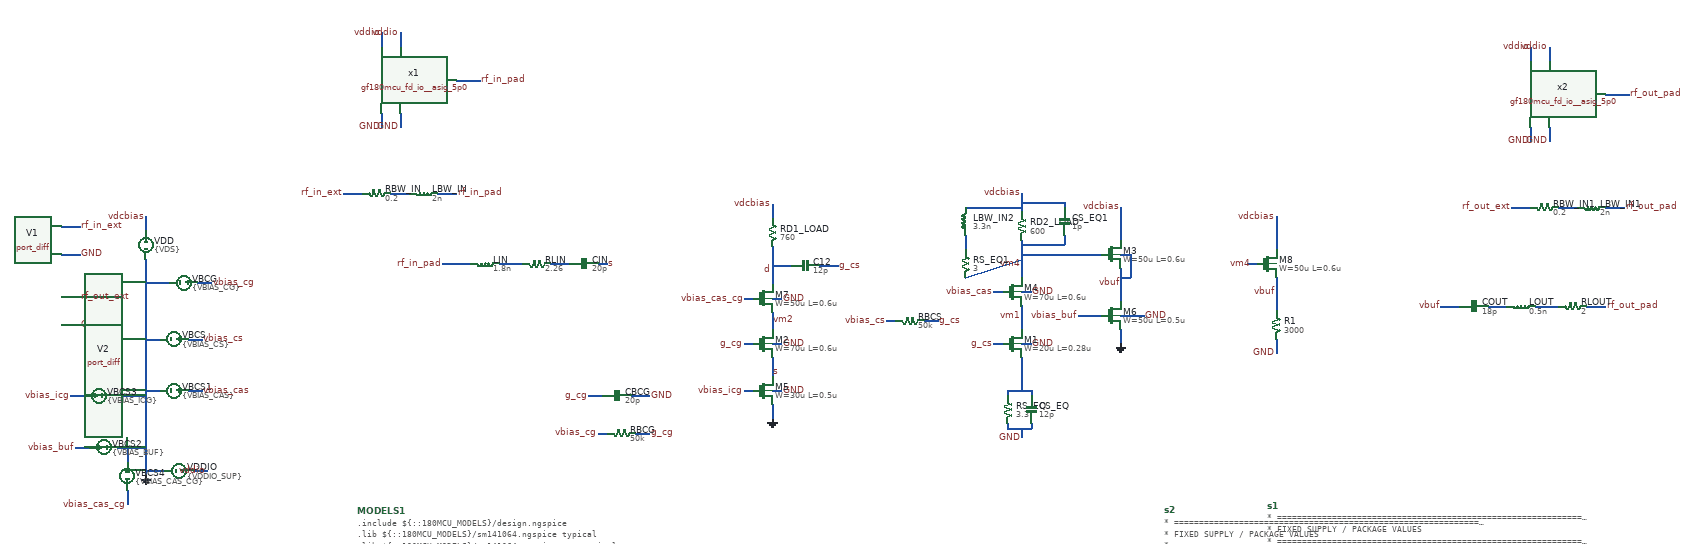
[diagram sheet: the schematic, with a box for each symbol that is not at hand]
v {xschem version=3.4.8RC file_version=1.3}
G {}
K {}
V {}
S {}
F {}
E {}
N -320 -440 -320 -410 {
lab=GND}
N 1010 -260 1030 -260 {
lab=GND}
N -320 -410 -320 -310 {
lab=GND}
N -320 -530 -320 -500 {
lab=vdcbias}
N -320 -390 -270 -390 {
lab=GND}
N -500 -510 -460 -510 {
lab=rf_in_ext}
N -500 -450 -460 -450 {
lab=GND}
N -500 -360 -460 -360 {
lab=rf_out_ext}
N -500 -300 -460 -300 {
lab=GND}
N 1010 -466.25 1010 -386.25 {
lab=d}
N 1010 -556.25 1010 -526.25 {
lab=vdcbias}
N -210 -390 -180 -390 {
lab=vbias_cg}
N 640 -430 660 -430 {
lab=s}
N 310 -430 340 -430 {
lab=rf_in_pad}
N 1010 -426.25 1050 -426.25 {
lab=d}
N 1110 -426.25 1150 -426.25 {
lab=g_cs}
N 1010 -230 1010 -220 {
lab=s}
N 1010 -220 1010 -190 {
lab=s}
N 950 -260 970 -260 {
lab=g_cg}
N -320 -310 -320 -110 {
lab=GND}
N 640 -70 660 -70 {
lab=vbias_cg}
N 720 -70 750 -70 {
lab=g_cg}
N 620 -150 650 -150 {
lab=g_cg}
N 710 -150 750 -150 {
lab=GND}
N 300 -580 340 -580 {
lab=rf_in_pad}
N 200 -580 240 -580 {
lab=rf_in_ext}
N 100 -580 140 -580 {
lab=rf_in_ext}
N 340 -820 390 -820 {
lab=rf_in_pad
}
N 180 -750 180 -720 {
lab=GND
}
N 220 -750 220 -720 {
lab=GND
}
N 180 -920 180 -890 {
lab=vddio
}
N 220 -920 220 -890 {
lab=vddio
}
N -320 -270 -290 -270 {
lab=GND}
N -220 10 -190 10 {
lab=vddio}
N 2780 -790 2830 -790 {
lab=rf_out_pad
}
N 2620 -720 2620 -690 {
lab=GND
}
N 2660 -720 2660 -690 {
lab=GND
}
N 2620 -890 2620 -860 {
lab=vddio
}
N 2660 -890 2660 -860 {
lab=vddio
}
N 2780 -550 2820 -550 {
lab=rf_out_pad}
N 2680 -550 2720 -550 {
lab=#net1}
N 2580 -550 2620 -550 {
lab=rf_out_ext}
N -320 10 -280 10 {
lab=GND}
N -230 -270 -200 -270 {
lab=vbias_cs}
N 1540 -260 1560 -260 {
lab=GND}
N 1540 -230 1540 -220 {
lab=#net2}
N 1480 -260 1500 -260 {
lab=g_cs}
N 1252.5 -308.75 1272.5 -308.75 {
lab=vbias_cs}
N 1332.5 -308.75 1362.5 -308.75 {
lab=g_cs}
N 1540 -220 1540 -160 {
lab=#net2}
N 1540 -580 1540 -540 {
lab=vdcbias}
N 1750 -550 1750 -480 {
lab=vdcbias
}
N 1750 -420 1750 -350 {
lab=vbuf
}
N 1750 -290 1750 -260 {
lab=GND
}
N 1750 -450 1770 -450 {
lab=vbuf
}
N 2430 -340 2470 -340 {
lab=vbuf}
N 2530 -340 2570 -340 {
lab=#net3}
N 2630 -340 2680 -340 {
lab=#net4}
N 2740 -340 2780 -340 {
lab=rf_out_pad}
N 340 -430 370 -430 {
lab=rf_in_pad}
N 430 -430 480 -430 {
lab=rf_in_pad}
N 540 -430 580 -430 {
lab=rf_in_pad}
N 1540 -370 1560 -370 {
lab=GND}
N 1480 -370 1500 -370 {
lab=vbias_cas}
N 1540 -480 1540 -400 {
lab=vm4}
N -320 -110 -320 20 {
lab=GND}
N -230 -160 -200 -160 {
lab=vbias_cas}
N -320 -160 -290 -160 {
lab=GND}
N 1770 -450 1770 -400 {
lab=vbuf
}
N 1750 -400 1770 -400 {
lab=vbuf
}
N 1010 -160 1030 -160 {
lab=GND}
N 1010 -130 1010 -120 {
lab=GND}
N 950 -160 970 -160 {
lab=vbias_icg}
N 1010 -120 1010 -100 {
lab=GND}
N 1660 -320 1710 -320 {
lab=vbias_buf
}
N 1750 -320 1800 -320 {
lab=GND
}
N -470 -40 -440 -40 {
lab=vbias_buf}
N -380 -40 -320 -40 {
lab=GND}
N -480 -150 -450 -150 {
lab=vbias_icg}
N -390 -150 -320 -150 {
lab=GND}
N 1560 -160 1560 -150 {
lab=#net2}
N 1510 -160 1560 -160 {
lab=#net2}
N 1560 -90 1560 -80 {
lab=GND}
N 1510 -80 1560 -80 {
lab=GND}
N 1510 -160 1510 -150 {
lab=#net2}
N 1510 -90 1510 -80 {
lab=GND}
N 1540 -80 1540 -60 {
lab=GND}
N 1670 -450 1710 -450 {
lab=vm4
}
N 1010 -356.25 1030 -356.25 {
lab=d}
N 951.25 -356.25 971.25 -356.25 {
lab=d}
N -360 51.25 -360 81.25 {
lab=vbias_cas_cg}
N 1540 -341.25 1540 -288.75 {
lab=vm1}
N 1010 -326.25 1010 -288.75 {
lab=d}
N -360 -40 -360 -8.75 {
lab=GND}
N 1540 -450 1670 -450 {
lab=vm4
spice_ignore=short}
N 2080 -530 2080 -460 {
lab=vdcbias
spice_ignore=true}
N 2080 -400 2080 -330 {
lab=vbuf
spice_ignore=true}
N 2020 -430 2040 -430 {lab=vm4
spice_ignore=true}
N 2080 -270 2080 -240 {lab=GND
spice_ignore=true}
N 1420 -550 1540 -550 {lab=vdcbias}
N 1540 -560 1630 -560 {lab=vdcbias}
N 1630 -560 1630 -550 {lab=vdcbias}
N 1630 -490 1630 -470 {lab=vm4}
N 1540 -470 1630 -470 {lab=vm4}
N 1420 -490 1420 -460 {lab=vm4}
N 1420 -400 1540 -440 {lab=vm4}
C {vsource.sym} -240 -390 1 0 {name=VBCG value=\{VBIAS_CG\} savecurrent=false}
C {gnd.sym} 1010 -100 0 0 {name=l1 lab=GND}
C {vsource.sym} -320 -470 0 0 {name=VDD value=\{VDS\} savecurrent=false}
C {capa.sym} 1080 -426.25 3 0 {name=C12
m=1
value=12p
footprint=1206
device="ceramic capacitor"}
C {lab_pin.sym} 1010 -416.25 0 0 {name=p3 sig_type=std_logic lab=d}
C {lab_pin.sym} -460 -510 2 0 {name=p5 sig_type=std_logic lab=rf_in_ext}
C {lab_pin.sym} -460 -450 2 0 {name=p6 sig_type=std_logic lab=GND

}
C {lab_pin.sym} -460 -300 2 0 {name=p8 sig_type=std_logic lab=GND}
C {capa.sym} 610 -430 3 0 {name=CIN
m=1
value=20p
footprint=1206
device="ceramic capacitor"}
C {gnd.sym} -320 20 0 0 {name=l3 lab=GND}
C {lab_pin.sym} -320 -530 0 0 {name=p10 sig_type=std_logic lab=vdcbias
}
C {lab_pin.sym} -180 -390 2 0 {name=p9 sig_type=std_logic lab=vbias_cg}
C {lab_pin.sym} 1010 -556.25 0 0 {name=p11 sig_type=std_logic lab=vdcbias
}
C {lab_pin.sym} 1150 -426.25 2 0 {name=p14 sig_type=std_logic lab=g_cs}
C {port_diff.sym} -500 -480 0 0 {name=V1 portnum=1 Z0=50 DCval=0 ACmag=1 ACphase=0 TRANval=""}
C {port_diff.sym} -500 -330 0 0 {name=V2 portnum=2 Z0=50 DCval=0 ACmag=1 ACphase=0 TRANval=""}
C {lab_pin.sym} 1010 -200 2 0 {name=p1 sig_type=std_logic lab=s}
C {lab_pin.sym} 1030 -260 2 0 {name=p2 sig_type=std_logic lab=GND}
C {code.sym} 1842.5 93.75 0 0 {name=s2 only_toplevel=false value="


* =============================================================================
* FIXED SUPPLY / PACKAGE VALUES
* =============================================================================

.param VDS=5.0
.param VDDIO_SUP=5.0
.param L_BW=2n
.param R_BW=0.2


* =============================================================================
* FIXED INPUT NETWORK
* =============================================================================

.param L_IN=1.80n
.param R_L_IN=1.5
.param CIN_VAL=100p
.param C_SH_IN=1f


* =============================================================================
* FIXED XM2 COMMON-GATE INPUT STAGE
* =============================================================================

.param VBIAS_CG=2.20
.param W_CG=140u
.param M_CG=2
.param L_CG=0.60u
.param RD1=760
.param RBIAS_CG=50k
.param CBYP_CG=20p


* =============================================================================
* FIXED MIXED-VOLTAGE XM1/XM4 STAGE
* =============================================================================

.param C12_VAL=33p

.param VBIAS_CS=1.05
.param W_CS=40u
.param M_CS=2
.param L_CS=0.28u
.param RBIAS_CS=50k

.param VBIAS_CAS=3.30
.param W_CAS=70u
.param M_CAS=1
.param L_CAS=0.60u
.param RD2=490

.param RS_EQ=7
.param CSEQ_VAL=12p


* =============================================================================
* FIXED BODY-TIED SOURCE FOLLOWER
* =============================================================================

.param W_SF=125u
.param M_SF=2
.param L_SF=0.60u
.param RG_SF_VAL=0.01


* =============================================================================
* FIXED OUTPUT NETWORK
* =============================================================================

.param COUT_VAL=56p
.param L_OUT=0.20n
.param R_L_OUT=1.5
.param C_SH_OUT=1f


* =============================================================================
* FIXED XM5 COMMON-GATE CURRENT SINK
* =============================================================================

.param VBIAS_ICG=1.55
.param L_BIAS_CG=0.50u
.param W_BIAS_CG=30u
.param M_BIAS_CG=1


* =============================================================================
* FIXED XM6 SOURCE-FOLLOWER CURRENT SINK
* =============================================================================

.param VBIAS_BUF=2.40
.param L_BIAS_SF=0.50u
.param W_BIAS_SF=50u
.param M_BIAS_SF=3


* =============================================================================
* XM7 CG-CASCODE SWEEP PARAMETERS
* =============================================================================

.param VBIAS_CAS_CG=3.40
.param L_CAS_CG=0.60u
.param W_CAS_CG=50u
.param M_CAS_CG=2

* =============================================================================
* NGSPICE-42 REPORT BLOCK FOR lna_core_06V_cgcs
* Based on the scalar-save and fresh-plot method from the supplied reference.
* No double quote characters are used.
* Replace the existing .control through .endc block with this block.
* =============================================================================

.control

set noaskquit
set wr_singlescale
set wr_vecnames
set numdgt=10

let target_gain_bw=10.0

echo ============================================================ > lna_core_06V_cgcs_report.txt
echo GF180MCU_LNA_CORE_06V_CGCS_DETAILED_REPORT >> lna_core_06V_cgcs_report.txt
echo TARGET_FREQUENCY_HZ 2.400e9 >> lna_core_06V_cgcs_report.txt
echo TARGET_BAND_HZ 2.300e9 2.500e9 >> lna_core_06V_cgcs_report.txt
echo GAIN_BANDWIDTH_THRESHOLD_DB 10.0 >> lna_core_06V_cgcs_report.txt
echo PORT_REFERENCE_OHM 50 >> lna_core_06V_cgcs_report.txt
echo ============================================================ >> lna_core_06V_cgcs_report.txt

* =============================================================================
* DC OPERATING POINT
* =============================================================================

op

let pdcop=1e3*(abs(i(VDD))*v(vdcbias)+abs(i(VDDIO))*v(vddio))
let icoreop=abs(i(VDD))
let iioop=abs(i(VDDIO))

let vsop=v(s)
let vdop=v(d)
let vnet3op=v(net3)
let vnet8op=v(net8)
let vbufop=v(vbuf)
let vgcsop=v(g_cs)
let vgcgop=v(g_cg)

let id1op=abs(@m.xm1.m0[id])
let gm1op=@m.xm1.m0[gm]
let gmb1op=@m.xm1.m0[gmbs]
let gds1op=@m.xm1.m0[gds]
let vgs1op=@m.xm1.m0[vgs]
let vds1op=@m.xm1.m0[vds]
let vbs1op=@m.xm1.m0[vbs]
let vth1op=@m.xm1.m0[vth]
let vov1op=vgs1op-vth1op
let vdsat1op=abs(@m.xm1.m0[vdsat])
let sat1op=vds1op-vdsat1op
let gmid1op=gm1op/(id1op+1e-30)
let ro1op=1/(gds1op+1e-30)

let id2op=abs(@m.xm2.m0[id])
let gm2op=@m.xm2.m0[gm]
let gmb2op=@m.xm2.m0[gmbs]
let gds2op=@m.xm2.m0[gds]
let vgs2op=@m.xm2.m0[vgs]
let vds2op=@m.xm2.m0[vds]
let vbs2op=@m.xm2.m0[vbs]
let vth2op=@m.xm2.m0[vth]
let vov2op=vgs2op-vth2op
let vdsat2op=abs(@m.xm2.m0[vdsat])
let sat2op=vds2op-vdsat2op
let gmid2op=gm2op/(id2op+1e-30)
let ro2op=1/(gds2op+1e-30)

let id3op=abs(@m.xm3.m0[id])
let gm3op=@m.xm3.m0[gm]
let gmb3op=@m.xm3.m0[gmbs]
let gds3op=@m.xm3.m0[gds]
let vgs3op=@m.xm3.m0[vgs]
let vds3op=@m.xm3.m0[vds]
let vbs3op=@m.xm3.m0[vbs]
let vth3op=@m.xm3.m0[vth]
let vov3op=vgs3op-vth3op
let vdsat3op=abs(@m.xm3.m0[vdsat])
let sat3op=vds3op-vdsat3op
let gmid3op=gm3op/(id3op+1e-30)
let ro3op=1/(gds3op+1e-30)

let id4op=abs(@m.xm4.m0[id])
let gm4op=@m.xm4.m0[gm]
let gmb4op=@m.xm4.m0[gmbs]
let gds4op=@m.xm4.m0[gds]
let vgs4op=@m.xm4.m0[vgs]
let vds4op=@m.xm4.m0[vds]
let vbs4op=@m.xm4.m0[vbs]
let vth4op=@m.xm4.m0[vth]
let vov4op=vgs4op-vth4op
let vdsat4op=abs(@m.xm4.m0[vdsat])
let sat4op=vds4op-vdsat4op
let gmid4op=gm4op/(id4op+1e-30)
let ro4op=1/(gds4op+1e-30)

let id5op=abs(@m.xm5.m0[id])
let gm5op=@m.xm5.m0[gm]
let gmb5op=@m.xm5.m0[gmbs]
let gds5op=@m.xm5.m0[gds]
let vgs5op=@m.xm5.m0[vgs]
let vds5op=@m.xm5.m0[vds]
let vbs5op=@m.xm5.m0[vbs]
let vth5op=@m.xm5.m0[vth]
let vov5op=vgs5op-vth5op
let vdsat5op=abs(@m.xm5.m0[vdsat])
let sat5op=vds5op-vdsat5op
let gmid5op=gm5op/(id5op+1e-30)
let ro5op=1/(gds5op+1e-30)

let id6op=abs(@m.xm6.m0[id])
let gm6op=@m.xm6.m0[gm]
let gmb6op=@m.xm6.m0[gmbs]
let gds6op=@m.xm6.m0[gds]
let vgs6op=@m.xm6.m0[vgs]
let vds6op=@m.xm6.m0[vds]
let vbs6op=@m.xm6.m0[vbs]
let vth6op=@m.xm6.m0[vth]
let vov6op=vgs6op-vth6op
let vdsat6op=abs(@m.xm6.m0[vdsat])
let sat6op=vds6op-vdsat6op
let gmid6op=gm6op/(id6op+1e-30)
let ro6op=1/(gds6op+1e-30)

let id7op=abs(@m.xm7.m0[id])
let gm7op=@m.xm7.m0[gm]
let gmb7op=@m.xm7.m0[gmbs]
let gds7op=@m.xm7.m0[gds]
let vgs7op=@m.xm7.m0[vgs]
let vds7op=@m.xm7.m0[vds]
let vbs7op=@m.xm7.m0[vbs]
let vth7op=@m.xm7.m0[vth]
let vov7op=vgs7op-vth7op
let vdsat7op=abs(@m.xm7.m0[vdsat])
let sat7op=vds7op-vdsat7op
let gmid7op=gm7op/(id7op+1e-30)
let ro7op=1/(gds7op+1e-30)

let vnet9op=vnet3op+vds1op
let vnet9check=vnet8op-vds4op
let vnet9diff=vnet9op-vnet9check
let vnet10op=vsop+vds2op
let vnet10check=vdop-vds7op
let vnet10diff=vnet10op-vnet10check

set op_pdc=$&pdcop
set op_icore=$&icoreop
set op_iio=$&iioop
set op_vs=$&vsop
set op_vnet10=$&vnet10op
set op_vnet10check=$&vnet10check
set op_vnet10diff=$&vnet10diff
set op_vd=$&vdop
set op_vnet3=$&vnet3op
set op_vnet9=$&vnet9op
set op_vnet9check=$&vnet9check
set op_vnet9diff=$&vnet9diff
set op_vnet8=$&vnet8op
set op_vbuf=$&vbufop
set op_vgcs=$&vgcsop
set op_vgcg=$&vgcgop

set op_id1=$&id1op
set op_gm1=$&gm1op
set op_gmb1=$&gmb1op
set op_gds1=$&gds1op
set op_vgs1=$&vgs1op
set op_vds1=$&vds1op
set op_vbs1=$&vbs1op
set op_vth1=$&vth1op
set op_vov1=$&vov1op
set op_vdsat1=$&vdsat1op
set op_sat1=$&sat1op
set op_gmid1=$&gmid1op
set op_ro1=$&ro1op

set op_id2=$&id2op
set op_gm2=$&gm2op
set op_gmb2=$&gmb2op
set op_gds2=$&gds2op
set op_vgs2=$&vgs2op
set op_vds2=$&vds2op
set op_vbs2=$&vbs2op
set op_vth2=$&vth2op
set op_vov2=$&vov2op
set op_vdsat2=$&vdsat2op
set op_sat2=$&sat2op
set op_gmid2=$&gmid2op
set op_ro2=$&ro2op

set op_id3=$&id3op
set op_gm3=$&gm3op
set op_gmb3=$&gmb3op
set op_gds3=$&gds3op
set op_vgs3=$&vgs3op
set op_vds3=$&vds3op
set op_vbs3=$&vbs3op
set op_vth3=$&vth3op
set op_vov3=$&vov3op
set op_vdsat3=$&vdsat3op
set op_sat3=$&sat3op
set op_gmid3=$&gmid3op
set op_ro3=$&ro3op

set op_id4=$&id4op
set op_gm4=$&gm4op
set op_gmb4=$&gmb4op
set op_gds4=$&gds4op
set op_vgs4=$&vgs4op
set op_vds4=$&vds4op
set op_vbs4=$&vbs4op
set op_vth4=$&vth4op
set op_vov4=$&vov4op
set op_vdsat4=$&vdsat4op
set op_sat4=$&sat4op
set op_gmid4=$&gmid4op
set op_ro4=$&ro4op

set op_id5=$&id5op
set op_gm5=$&gm5op
set op_gmb5=$&gmb5op
set op_gds5=$&gds5op
set op_vgs5=$&vgs5op
set op_vds5=$&vds5op
set op_vbs5=$&vbs5op
set op_vth5=$&vth5op
set op_vov5=$&vov5op
set op_vdsat5=$&vdsat5op
set op_sat5=$&sat5op
set op_gmid5=$&gmid5op
set op_ro5=$&ro5op

set op_id6=$&id6op
set op_gm6=$&gm6op
set op_gmb6=$&gmb6op
set op_gds6=$&gds6op
set op_vgs6=$&vgs6op
set op_vds6=$&vds6op
set op_vbs6=$&vbs6op
set op_vth6=$&vth6op
set op_vov6=$&vov6op
set op_vdsat6=$&vdsat6op
set op_sat6=$&sat6op
set op_gmid6=$&gmid6op
set op_ro6=$&ro6op

set op_id7=$&id7op
set op_gm7=$&gm7op
set op_gmb7=$&gmb7op
set op_gds7=$&gds7op
set op_vgs7=$&vgs7op
set op_vds7=$&vds7op
set op_vbs7=$&vbs7op
set op_vth7=$&vth7op
set op_vov7=$&vov7op
set op_vdsat7=$&vdsat7op
set op_sat7=$&sat7op
set op_gmid7=$&gmid7op
set op_ro7=$&ro7op

echo ============================================================ >> lna_core_06V_cgcs_report.txt
echo DC_SUPPLY_AND_NODE_VOLTAGES >> lna_core_06V_cgcs_report.txt
echo PDC_mW $op_pdc ICORE_A $op_icore IIO_A $op_iio >> lna_core_06V_cgcs_report.txt
echo NODES_V S $op_vs NET10_DERIVED $op_vnet10 D $op_vd NET3 $op_vnet3 NET9_DERIVED $op_vnet9 NET8 $op_vnet8 VBUF $op_vbuf G_CS $op_vgcs G_CG $op_vgcg >> lna_core_06V_cgcs_report.txt
echo HIDDEN_NODE_CHECKS NET10_FROM_XM2 $op_vnet10 NET10_FROM_XM7 $op_vnet10check DIFFERENCE $op_vnet10diff NET9_FROM_XM1 $op_vnet9 NET9_FROM_XM4 $op_vnet9check DIFFERENCE $op_vnet9diff >> lna_core_06V_cgcs_report.txt
echo ============================================================ >> lna_core_06V_cgcs_report.txt
echo TRANSISTOR_OPERATING_POINTS >> lna_core_06V_cgcs_report.txt
echo FIELDS ID_A GM_S GMBS_S GDS_S VGS_V VDS_V VBS_V VTH_V VOV_V VDSAT_V SAT_MARGIN_V GM_OVER_ID_1_PER_V RO_OHM >> lna_core_06V_cgcs_report.txt
echo XM1_CS ID $op_id1 GM $op_gm1 GMBS $op_gmb1 GDS $op_gds1 VGS $op_vgs1 VDS $op_vds1 VBS $op_vbs1 VTH $op_vth1 VOV $op_vov1 VDSAT $op_vdsat1 SAT_MARGIN $op_sat1 GMID $op_gmid1 RO $op_ro1 >> lna_core_06V_cgcs_report.txt
echo XM2_CG ID $op_id2 GM $op_gm2 GMBS $op_gmb2 GDS $op_gds2 VGS $op_vgs2 VDS $op_vds2 VBS $op_vbs2 VTH $op_vth2 VOV $op_vov2 VDSAT $op_vdsat2 SAT_MARGIN $op_sat2 GMID $op_gmid2 RO $op_ro2 >> lna_core_06V_cgcs_report.txt
echo XM3_SOURCE_FOLLOWER ID $op_id3 GM $op_gm3 GMBS $op_gmb3 GDS $op_gds3 VGS $op_vgs3 VDS $op_vds3 VBS $op_vbs3 VTH $op_vth3 VOV $op_vov3 VDSAT $op_vdsat3 SAT_MARGIN $op_sat3 GMID $op_gmid3 RO $op_ro3 >> lna_core_06V_cgcs_report.txt
echo XM4_CS_CASCODE ID $op_id4 GM $op_gm4 GMBS $op_gmb4 GDS $op_gds4 VGS $op_vgs4 VDS $op_vds4 VBS $op_vbs4 VTH $op_vth4 VOV $op_vov4 VDSAT $op_vdsat4 SAT_MARGIN $op_sat4 GMID $op_gmid4 RO $op_ro4 >> lna_core_06V_cgcs_report.txt
echo XM5_CG_CURRENT_SINK ID $op_id5 GM $op_gm5 GMBS $op_gmb5 GDS $op_gds5 VGS $op_vgs5 VDS $op_vds5 VBS $op_vbs5 VTH $op_vth5 VOV $op_vov5 VDSAT $op_vdsat5 SAT_MARGIN $op_sat5 GMID $op_gmid5 RO $op_ro5 >> lna_core_06V_cgcs_report.txt
echo XM6_BUFFER_CURRENT_SINK ID $op_id6 GM $op_gm6 GMBS $op_gmb6 GDS $op_gds6 VGS $op_vgs6 VDS $op_vds6 VBS $op_vbs6 VTH $op_vth6 VOV $op_vov6 VDSAT $op_vdsat6 SAT_MARGIN $op_sat6 GMID $op_gmid6 RO $op_ro6 >> lna_core_06V_cgcs_report.txt
echo XM7_CG_CASCODE ID $op_id7 GM $op_gm7 GMBS $op_gmb7 GDS $op_gds7 VGS $op_vgs7 VDS $op_vds7 VBS $op_vbs7 VTH $op_vth7 VOV $op_vov7 VDSAT $op_vdsat7 SAT_MARGIN $op_sat7 GMID $op_gmid7 RO $op_ro7 >> lna_core_06V_cgcs_report.txt

destroy $curplot

* =============================================================================
* SINGLE BROADBAND RF ANALYSIS
* One reset and one SP run are used for all 1 MHz to 7 GHz RF results.
* Target-band values are extracted from the same dataset.
* This avoids inconsistent port excitation state between repeated SP runs.
* 7000 points from 1 MHz to 7 GHz gives exactly 1 MHz spacing.
* =============================================================================

reset
sp lin 7000 1Meg 7Gig 1
set rfplot=$curplot

let fghz=frequency/1e9

let s11db=db(s_1_1)
let s21db=db(s_2_1)
let s12db=db(s_1_2)
let s22db=db(s_2_2)

let s11re=real(s_1_1)
let s11im=imag(s_1_1)
let s21re=real(s_2_1)
let s21im=imag(s_2_1)
let s12re=real(s_1_2)
let s12im=imag(s_1_2)
let s22re=real(s_2_2)
let s22im=imag(s_2_2)

let nfdb=real(NF)
let nfmin_db=real(NFmin)

let delta=s_1_1*s_2_2-s_1_2*s_2_1
let delta_mag=mag(delta)
let a11=mag(s_1_1)
let a12=mag(s_1_2)
let a21=mag(s_2_1)
let a22=mag(s_2_2)
let mu=(1-a11*a11)/(mag(s_2_2-delta*conj(s_1_1))+mag(s_1_2*s_2_1))
let mup=(1-a22*a22)/(mag(s_1_1-delta*conj(s_2_2))+mag(s_1_2*s_2_1))
let kval=(1-a11*a11-a22*a22+delta_mag*delta_mag)/(2*a12*a21)

let zin=50*(1+s_1_1)/(1-s_1_1)
let zout=50*(1+s_2_2)/(1-s_2_2)
let zin_re=real(zin)
let zin_im=imag(zin)
let zout_re=real(zout)
let zout_im=imag(zout)

let npts=length(frequency)

* Find indices nearest 2.300 GHz, 2.400 GHz and 2.500 GHz.
let ilo=0
let icenter=0
let ihi=0
let errlo=abs(frequency[0]-2.3e9)
let errcenter=abs(frequency[0]-2.4e9)
let errhi=abs(frequency[0]-2.5e9)
let ii=1
while ii < npts
let newerr=abs(frequency[ii]-2.3e9)
if newerr < errlo
let errlo=newerr
let ilo=ii
end
let newerr=abs(frequency[ii]-2.4e9)
if newerr < errcenter
let errcenter=newerr
let icenter=ii
end
let newerr=abs(frequency[ii]-2.5e9)
if newerr < errhi
let errhi=newerr
let ihi=ii
end
let ii=ii+1
end

* Values at the sample nearest 2.400 GHz.
let center_freq=frequency[icenter]
let s11c=s11db[icenter]
let s21c=s21db[icenter]
let s12c=s12db[icenter]
let s22c=s22db[icenter]
let s11rc=s11re[icenter]
let s11ic=s11im[icenter]
let s21rc=s21re[icenter]
let s21ic=s21im[icenter]
let s12rc=s12re[icenter]
let s12ic=s12im[icenter]
let s22rc=s22re[icenter]
let s22ic=s22im[icenter]
let nfc=nfdb[icenter]
let nfminc=nfmin_db[icenter]
let muc=mu[icenter]
let mupc=mup[icenter]
let kc=kval[icenter]
let dmc=delta_mag[icenter]
let zinrc=zin_re[icenter]
let zinic=zin_im[icenter]
let zoutrc=zout_re[icenter]
let zoutic=zout_im[icenter]

* Initialize target-band extrema.
let s11min=s11db[ilo]
let s11max=s11db[ilo]
let s21min=s21db[ilo]
let s21max=s21db[ilo]
let s12min=s12db[ilo]
let s12max=s12db[ilo]
let s22min=s22db[ilo]
let s22max=s22db[ilo]
let nfbandmin=nfdb[ilo]
let nfbandmax=nfdb[ilo]
let nfminbandmin=nfmin_db[ilo]
let nfminbandmax=nfmin_db[ilo]
let mumin=mu[ilo]
let mupmin=mup[ilo]
let kmin=kval[ilo]
let dmax=delta_mag[ilo]

let s11min_i=ilo
let s11max_i=ilo
let s21min_i=ilo
let s21max_i=ilo
let s12min_i=ilo
let s12max_i=ilo
let s22min_i=ilo
let s22max_i=ilo
let nfmin_i=ilo
let nfmax_i=ilo
let nfminpar_min_i=ilo
let nfminpar_max_i=ilo
let mumin_i=ilo
let mupmin_i=ilo
let kmin_i=ilo
let dmax_i=ilo

* Scan 2.300 GHz to 2.500 GHz.
let ii=ilo
while ii <= ihi
if s11db[ii] < s11min
let s11min=s11db[ii]
let s11min_i=ii
end
if s11db[ii] > s11max
let s11max=s11db[ii]
let s11max_i=ii
end
if s21db[ii] < s21min
let s21min=s21db[ii]
let s21min_i=ii
end
if s21db[ii] > s21max
let s21max=s21db[ii]
let s21max_i=ii
end
if s12db[ii] < s12min
let s12min=s12db[ii]
let s12min_i=ii
end
if s12db[ii] > s12max
let s12max=s12db[ii]
let s12max_i=ii
end
if s22db[ii] < s22min
let s22min=s22db[ii]
let s22min_i=ii
end
if s22db[ii] > s22max
let s22max=s22db[ii]
let s22max_i=ii
end
if nfdb[ii] < nfbandmin
let nfbandmin=nfdb[ii]
let nfmin_i=ii
end
if nfdb[ii] > nfbandmax
let nfbandmax=nfdb[ii]
let nfmax_i=ii
end
if nfmin_db[ii] < nfminbandmin
let nfminbandmin=nfmin_db[ii]
let nfminpar_min_i=ii
end
if nfmin_db[ii] > nfminbandmax
let nfminbandmax=nfmin_db[ii]
let nfminpar_max_i=ii
end
if mu[ii] < mumin
let mumin=mu[ii]
let mumin_i=ii
end
if mup[ii] < mupmin
let mupmin=mup[ii]
let mupmin_i=ii
end
if kval[ii] < kmin
let kmin=kval[ii]
let kmin_i=ii
end
if delta_mag[ii] > dmax
let dmax=delta_mag[ii]
let dmax_i=ii
end
let ii=ii+1
end

let gain_ripple=s21max-s21min

let s11min_f=frequency[s11min_i]
let s11max_f=frequency[s11max_i]
let s21min_f=frequency[s21min_i]
let s21max_f=frequency[s21max_i]
let s12min_f=frequency[s12min_i]
let s12max_f=frequency[s12max_i]
let s22min_f=frequency[s22min_i]
let s22max_f=frequency[s22max_i]
let nfmin_f=frequency[nfmin_i]
let nfmax_f=frequency[nfmax_i]
let nfminpar_min_f=frequency[nfminpar_min_i]
let nfminpar_max_f=frequency[nfminpar_max_i]
let mumin_f=frequency[mumin_i]
let mupmin_f=frequency[mupmin_i]
let kmin_f=frequency[kmin_i]
let dmax_f=frequency[dmax_i]

* Find the broadband S21 peak and its index.
let imax=0
let gainmax=s21db[0]
let ii=1
while ii < npts
if s21db[ii] > gainmax
let gainmax=s21db[ii]
let imax=ii
end
let ii=ii+1
end
let peakfreq=frequency[imax]

echo ============================================================ >> lna_core_06V_cgcs_report.txt
echo RF_AT_2P400_GHZ_FROM_SINGLE_BROADBAND_SWEEP >> lna_core_06V_cgcs_report.txt
echo ACTUAL_SAMPLE_HZ $&center_freq >> lna_core_06V_cgcs_report.txt
echo S11_DB $&s11c REAL $&s11rc IMAG $&s11ic >> lna_core_06V_cgcs_report.txt
echo S21_DB $&s21c REAL $&s21rc IMAG $&s21ic >> lna_core_06V_cgcs_report.txt
echo S12_DB $&s12c REAL $&s12rc IMAG $&s12ic >> lna_core_06V_cgcs_report.txt
echo S22_DB $&s22c REAL $&s22rc IMAG $&s22ic >> lna_core_06V_cgcs_report.txt
echo NF_DB $&nfc NFMIN_DB $&nfminc >> lna_core_06V_cgcs_report.txt
echo MU $&muc MUP $&mupc K $&kc DELTA_MAG $&dmc >> lna_core_06V_cgcs_report.txt
echo ZIN_OHM RE $&zinrc IM $&zinic >> lna_core_06V_cgcs_report.txt
echo ZOUT_OHM RE $&zoutrc IM $&zoutic >> lna_core_06V_cgcs_report.txt

echo ============================================================ >> lna_core_06V_cgcs_report.txt
echo RF_MIN_MAX_FROM_2P300_TO_2P500_GHZ >> lna_core_06V_cgcs_report.txt
echo S11_MIN_DB $&s11min AT_HZ $&s11min_f S11_MAX_DB $&s11max AT_HZ $&s11max_f >> lna_core_06V_cgcs_report.txt
echo S21_MIN_DB $&s21min AT_HZ $&s21min_f S21_MAX_DB $&s21max AT_HZ $&s21max_f GAIN_RIPPLE_DB $&gain_ripple >> lna_core_06V_cgcs_report.txt
echo S12_MIN_DB $&s12min AT_HZ $&s12min_f S12_MAX_DB $&s12max AT_HZ $&s12max_f >> lna_core_06V_cgcs_report.txt
echo S22_MIN_DB $&s22min AT_HZ $&s22min_f S22_MAX_DB $&s22max AT_HZ $&s22max_f >> lna_core_06V_cgcs_report.txt
echo NF_MIN_DB $&nfbandmin AT_HZ $&nfmin_f NF_MAX_DB $&nfbandmax AT_HZ $&nfmax_f >> lna_core_06V_cgcs_report.txt
echo NFMIN_PARAMETER_MIN_DB $&nfminbandmin AT_HZ $&nfminpar_min_f NFMIN_PARAMETER_MAX_DB $&nfminbandmax AT_HZ $&nfminpar_max_f >> lna_core_06V_cgcs_report.txt
echo MU_MIN $&mumin AT_HZ $&mumin_f MUP_MIN $&mupmin AT_HZ $&mupmin_f >> lna_core_06V_cgcs_report.txt
echo K_MIN $&kmin AT_HZ $&kmin_f DELTA_MAX $&dmax AT_HZ $&dmax_f >> lna_core_06V_cgcs_report.txt

echo ============================================================ >> lna_core_06V_cgcs_report.txt
echo BROADBAND_GAIN_CHECK_1MHZ_TO_7GHZ >> lna_core_06V_cgcs_report.txt
echo GAIN_AT_2P4_DB $&s21c >> lna_core_06V_cgcs_report.txt
echo BROADBAND_PEAK_HZ $&peakfreq PEAK_GAIN_DB $&gainmax >> lna_core_06V_cgcs_report.txt

echo ============================================================ >> lna_core_06V_cgcs_report.txt
echo TARGET_CENTERED_S21_GE_10DB_BAND >> lna_core_06V_cgcs_report.txt
if s21c >= 10.0
let bwlo=icenter
let bwhi=icenter
let search=1
while search = 1
if bwlo > 0
if s21db[bwlo-1] >= 10.0
let bwlo=bwlo-1
else
let search=0
end
else
let search=0
end
end
let search=1
while search = 1
if bwhi < npts-1
if s21db[bwhi+1] >= 10.0
let bwhi=bwhi+1
else
let search=0
end
else
let search=0
end
end
let bwflo=frequency[bwlo]
let bwfhi=frequency[bwhi]
let bwval=bwfhi-bwflo
let bwcenter=0.5*(bwfhi+bwflo)
let bwfbw=100*bwval/(bwcenter+1e-30)
echo LOWER_HZ $&bwflo UPPER_HZ $&bwfhi BANDWIDTH_HZ $&bwval BAND_CENTER_HZ $&bwcenter FRACTIONAL_BW_PERCENT $&bwfbw >> lna_core_06V_cgcs_report.txt
else
echo NO_VALID_TARGET_CENTERED_BAND S21_AT_2P4_DB $&s21c >> lna_core_06V_cgcs_report.txt
end

echo ============================================================ >> lna_core_06V_cgcs_report.txt
echo GLOBAL_CONTIGUOUS_S21_GE_10DB_BAND_AROUND_PEAK >> lna_core_06V_cgcs_report.txt
if gainmax >= 10.0
let bwlo=imax
let bwhi=imax
let search=1
while search = 1
if bwlo > 0
if s21db[bwlo-1] >= 10.0
let bwlo=bwlo-1
else
let search=0
end
else
let search=0
end
end
let search=1
while search = 1
if bwhi < npts-1
if s21db[bwhi+1] >= 10.0
let bwhi=bwhi+1
else
let search=0
end
else
let search=0
end
end
let bwflo=frequency[bwlo]
let bwfhi=frequency[bwhi]
let bwval=bwfhi-bwflo
let bwcenter=0.5*(bwfhi+bwflo)
let bwfbw=100*bwval/(bwcenter+1e-30)
echo LOWER_HZ $&bwflo UPPER_HZ $&bwfhi BANDWIDTH_HZ $&bwval BAND_CENTER_HZ $&bwcenter FRACTIONAL_BW_PERCENT $&bwfbw >> lna_core_06V_cgcs_report.txt
else
echo NO_S21_ABOVE_10DB_FROM_1MHZ_TO_7GHZ PEAK_GAIN_DB $&gainmax PEAK_FREQUENCY_HZ $&peakfreq >> lna_core_06V_cgcs_report.txt
end

wrdata lna_core_06V_cgcs_target_band.dat frequency s_1_1 s_2_1 s_1_2 s_2_2 s11db s21db s12db s22db nfdb nfmin_db kval mu mup delta_mag zin_re zin_im zout_re zout_im
wrdata lna_core_06V_cgcs_broadband.dat frequency s11db s21db s12db s22db nfdb nfmin_db kval mu mup delta_mag zin_re zin_im zout_re zout_im

* =============================================================================
* WIDEBAND STABILITY 10 MHZ TO 30 GHZ
* =============================================================================

sp dec 101 10Meg 30G 1
set stabilityplot=$curplot

let wbdelta=s_1_1*s_2_2-s_1_2*s_2_1
let wbmd=mag(wbdelta)
let wba11=mag(s_1_1)
let wba12=mag(s_1_2)
let wba21=mag(s_2_1)
let wba22=mag(s_2_2)
let wbmu=(1-wba11*wba11)/(mag(s_2_2-wbdelta*conj(s_1_1))+mag(s_1_2*s_2_1))
let wbmup=(1-wba22*wba22)/(mag(s_1_1-wbdelta*conj(s_2_2))+mag(s_1_2*s_2_1))
let wbk=(1-wba11*wba11-wba22*wba22+wbmd*wbmd)/(2*wba12*wba21)

let wbkmin=minimum(wbk)
let wbmumin=minimum(wbmu)
let wbmupmin=minimum(wbmup)
let wbdmax=maximum(wbmd)

set final_wbkmin=$&wbkmin
set final_wbmumin=$&wbmumin
set final_wbmupmin=$&wbmupmin
set final_wbdmax=$&wbdmax

echo ============================================================ >> lna_core_06V_cgcs_report.txt
echo WIDEBAND_STABILITY_10MHZ_TO_30GHZ >> lna_core_06V_cgcs_report.txt
echo K_MIN $final_wbkmin MU_MIN $final_wbmumin MUP_MIN $final_wbmupmin DELTA_MAX $final_wbdmax >> lna_core_06V_cgcs_report.txt

wrdata lna_core_06V_cgcs_stability.dat frequency wbk wbmu wbmup wbmd

let wbfghz=frequency/1e9

echo ============================================================ >> lna_core_06V_cgcs_report.txt
echo OUTPUT_FILES >> lna_core_06V_cgcs_report.txt
echo REPORT lna_core_06V_cgcs_report.txt >> lna_core_06V_cgcs_report.txt
echo TARGET_DATA lna_core_06V_cgcs_target_band.dat >> lna_core_06V_cgcs_report.txt
echo BROADBAND_DATA lna_core_06V_cgcs_broadband.dat >> lna_core_06V_cgcs_report.txt
echo STABILITY_DATA lna_core_06V_cgcs_stability.dat >> lna_core_06V_cgcs_report.txt
echo PLOTS S11_S21_S12_S22_SEPARATE NF_AND_NFMIN_TOGETHER STABILITY_AND_IMPEDANCE_DIAGNOSTICS >> lna_core_06V_cgcs_report.txt
echo ============================================================ >> lna_core_06V_cgcs_report.txt



* =============================================================================
* VISIBLE PLOTS
* Plot commands are intentionally placed at the very end.
* Neither rfplot nor stabilityplot is destroyed or reset afterward.
* =============================================================================

setplot $rfplot
setscale fghz

* Target band 2.3 GHz to 2.5 GHz
plot s11db xlimit 2.3 2.5
plot s21db xlimit 2.3 2.5
plot s12db xlimit 2.3 2.5
plot s22db xlimit 2.3 2.5
plot nfdb nfmin_db xlimit 2.3 2.5
*plot mu mup xlimit 2.3 2.5
*plot kval xlimit 2.3 2.5
*plot delta_mag xlimit 2.3 2.5
*plot zin_re zin_im xlimit 2.3 2.5
*plot zout_re zout_im xlimit 2.3 2.5

* Broadband 1 MHz to 7 GHz
plot s11db xlimit 0 7
plot s21db xlimit 0 7
plot s12db xlimit 0 7
plot s22db xlimit 0 7
plot nfdb nfmin_db xlimit 0 7
*plot mu mup xlimit 0 7
*plot kval xlimit 0 7
*plot delta_mag xlimit 0 7
*plot zin_re zin_im xlimit 0 7
*plot zout_re zout_im xlimit 0 7

* Wideband stability 10 MHz to 30 GHz
*setplot $stabilityplot
*setscale wbfghz
*plot wbmu wbmup
*plot wbk
*plot wbmd

.endc

"
}
C {symbols/nfet_06v0.sym} 990 -260 0 0 {name=M2
L=0.6u
W=70u
nf=10
m=5
ad="'int((nf+1)/2) * W/nf * 0.18u'"
pd="'2*int((nf+1)/2) * (W/nf + 0.18u)'"
as="'int((nf+2)/2) * W/nf * 0.18u'"
ps="'2*int((nf+2)/2) * (W/nf + 0.18u)'"
nrd="'0.18u / W'" nrs="'0.18u / W'"
sa=0 sb=0 sd=0
model=nfet_06v0
spiceprefix=X
}
C {lab_pin.sym} 660 -430 2 0 {name=p17 sig_type=std_logic lab=s}
C {res.sym} 690 -70 1 0 {name=RBCG
value=50k
footprint=1206
device=resistor
m=1}
C {lab_pin.sym} 640 -70 0 0 {name=p20 sig_type=std_logic lab=vbias_cg}
C {lab_pin.sym} 750 -70 2 0 {name=p21 sig_type=std_logic lab=g_cg}
C {capa.sym} 680 -150 3 0 {name=CBCG
m=1
value=20p
footprint=1206
device="ceramic capacitor"}
C {lab_pin.sym} 750 -150 2 0 {name=p19 sig_type=std_logic lab=GND}
C {ind.sym} 270 -580 1 0 {name=LBW_IN
m=1
value=2n
footprint=1206
device=inductor}
C {res.sym} 170 -580 1 0 {name=RBW_IN
value=0.2
footprint=1206
device=resistor
m=1
spice_ignore=short}
C {lab_pin.sym} 100 -580 0 0 {name=p22 sig_type=std_logic lab=rf_in_ext}
C {lab_pin.sym} 340 -580 2 0 {name=p25 sig_type=std_logic lab=rf_in_pad}
C {lab_pin.sym} 390 -820 2 0 {name=p26 sig_type=std_logic lab=rf_in_pad
}
C {vsource.sym} -250 10 1 0 {name=VDDIO value=\{VDDIO_SUP\} savecurrent=false}
C {lab_pin.sym} -190 10 1 0 {name=p27 sig_type=std_logic lab=vddio
}
C {lab_pin.sym} 180 -920 1 0 {name=p28 sig_type=std_logic lab=vddio
}
C {lab_pin.sym} 220 -920 1 0 {name=p29 sig_type=std_logic lab=vddio
}
C {lab_pin.sym} 180 -720 3 0 {name=p30 sig_type=std_logic lab=GND
}
C {lab_pin.sym} 220 -720 3 0 {name=p31 sig_type=std_logic lab=GND
}
C {lab_pin.sym} 310 -430 0 0 {name=p13 sig_type=std_logic lab=rf_in_pad}
C {lab_pin.sym} 2620 -890 1 0 {name=p33 sig_type=std_logic lab=vddio
}
C {lab_pin.sym} 2660 -890 1 0 {name=p34 sig_type=std_logic lab=vddio
}
C {lab_pin.sym} 2620 -690 3 0 {name=p35 sig_type=std_logic lab=GND
}
C {lab_pin.sym} 2660 -690 3 0 {name=p36 sig_type=std_logic lab=GND
}
C {lab_pin.sym} 2830 -790 2 0 {name=p32 sig_type=std_logic lab=rf_out_pad
}
C {ind.sym} 2750 -550 1 0 {name=LBW_IN1
m=1
value=2n
footprint=1206
device=inductor}
C {res.sym} 2650 -550 1 0 {name=RBW_IN1
value=0.2
footprint=1206
device=resistor
m=1}
C {lab_pin.sym} 2580 -550 0 0 {name=p37 sig_type=std_logic lab=rf_out_ext}
C {lab_pin.sym} 2820 -550 2 0 {name=p38 sig_type=std_logic lab=rf_out_pad}
C {lab_pin.sym} -460 -360 2 0 {name=p7 sig_type=std_logic lab=rf_out_ext}
C {vsource.sym} -260 -270 1 0 {name=VBCS value=\{VBIAS_CS\} savecurrent=false}
C {lab_pin.sym} -200 -270 2 0 {name=p12 sig_type=std_logic lab=vbias_cs}
C {lab_pin.sym} 950 -260 0 0 {name=p4 sig_type=std_logic lab=g_cg}
C {lab_pin.sym} 620 -150 0 0 {name=p15 sig_type=std_logic lab=g_cg}
C {res.sym} 1010 -496.25 0 0 {name=RD1_LOAD
value=760
footprint=1206
device=resistor
m=1
}
C {lab_pin.sym} 1540 -60 3 0 {name=p16 sig_type=std_logic lab=GND}
C {lab_pin.sym} 1480 -260 0 0 {name=p18 sig_type=std_logic lab=g_cs}
C {res.sym} 1302.5 -308.75 1 0 {name=RBCS
value=50k
footprint=1206
device=resistor
m=1}
C {lab_pin.sym} 1252.5 -308.75 0 0 {name=p23 sig_type=std_logic lab=vbias_cs}
C {lab_pin.sym} 1362.5 -308.75 2 0 {name=p24 sig_type=std_logic lab=g_cs}
C {res.sym} 1540 -510 0 0 {name=RD2_LOAD
value=600
footprint=1206
device=resistor
m=1
}
C {lab_pin.sym} 1540 -580 0 0 {name=p39 sig_type=std_logic lab=vdcbias
}
C {symbols/nfet_06v0.sym} 1730 -450 0 0 {name=M3
L=0.6u
W=50u
nf=10
m=5
ad="'int((nf+1)/2) * W/nf * 0.18u'"
pd="'2*int((nf+1)/2) * (W/nf + 0.18u)'"
as="'int((nf+2)/2) * W/nf * 0.18u'"
ps="'2*int((nf+2)/2) * (W/nf + 0.18u)'"
nrd="'0.18u / W'" nrs="'0.18u / W'"
sa=0 sb=0 sd=0
model=nfet_06v0
spiceprefix=X
}
C {lab_pin.sym} 1750 -550 0 0 {name=p40 sig_type=std_logic lab=vdcbias
}
C {gnd.sym} 1750 -260 0 0 {name=l2 lab=GND
}
C {capa.sym} 2500 -340 3 0 {name=COUT
m=1
value=18p
footprint=1206
device="ceramic capacitor"}
C {lab_pin.sym} 1750 -390 0 0 {name=p43 sig_type=std_logic lab=vbuf
}
C {lab_pin.sym} 2430 -340 0 0 {name=p44 sig_type=std_logic lab=vbuf}
C {lab_pin.sym} 2780 -340 2 0 {name=p45 sig_type=std_logic lab=rf_out_pad}
C {ind.sym} 2600 -340 1 0 {name=LOUT
m=1
value=0.5n
footprint=1206
device=inductor
}
C {res.sym} 2710 -340 1 0 {name=RLOUT
value=2
footprint=1206
device=resistor
m=1}
C {ind.sym} 400 -430 1 0 {name=LIN
m=1
value=1.8n
footprint=1206
device=inductor
spice_ignore=short}
C {res.sym} 510 -430 1 0 {name=RLIN
value=2.26
footprint=1206
device=resistor
m=1
spice_ignore=short}
C {symbols/nfet_06v0.sym} 1520 -370 0 0 {name=M4
L=0.6u
W=70u
nf=10
m=1
ad="'int((nf+1)/2) * W/nf * 0.18u'"
pd="'2*int((nf+1)/2) * (W/nf + 0.18u)'"
as="'int((nf+2)/2) * W/nf * 0.18u'"
ps="'2*int((nf+2)/2) * (W/nf + 0.18u)'"
nrd="'0.18u / W'" nrs="'0.18u / W'"
sa=0 sb=0 sd=0
model=nfet_06v0
spiceprefix=X
}
C {lab_pin.sym} 1480 -370 0 0 {name=p47 sig_type=std_logic lab=vbias_cas}
C {lab_pin.sym} 1560 -370 2 0 {name=p48 sig_type=std_logic lab=GND}
C {vsource.sym} -260 -160 1 0 {name=VBCS1 value=\{VBIAS_CAS\} savecurrent=false}
C {lab_pin.sym} -200 -160 2 0 {name=p49 sig_type=std_logic lab=vbias_cas}
C {lab_pin.sym} 1030 -160 2 0 {name=p41 sig_type=std_logic lab=GND}
C {lab_pin.sym} 950 -160 0 0 {name=p50 sig_type=std_logic lab=vbias_icg}
C {lab_pin.sym} 1660 -320 0 0 {name=p51 sig_type=std_logic lab=vbias_buf
}
C {lab_pin.sym} 1800 -320 2 0 {name=p52 sig_type=std_logic lab=GND
}
C {vsource.sym} -410 -40 3 0 {name=VBCS2 value=\{VBIAS_BUF\} savecurrent=false}
C {lab_pin.sym} -470 -40 0 0 {name=p53 sig_type=std_logic lab=vbias_buf}
C {vsource.sym} -420 -150 3 0 {name=VBCS3 value=\{VBIAS_ICG\} savecurrent=false}
C {lab_pin.sym} -480 -150 0 0 {name=p54 sig_type=std_logic lab=vbias_icg}
C {symbols/nfet_03v3.sym} 990 -160 0 0 {name=M5
L=0.5u
W=30u
nf=10
m=1
ad="'int((nf+1)/2) * W/nf * 0.18u'"
pd="'2*int((nf+1)/2) * (W/nf + 0.18u)'"
as="'int((nf+2)/2) * W/nf * 0.18u'"
ps="'2*int((nf+2)/2) * (W/nf + 0.18u)'"
nrd="'0.18u / W'" nrs="'0.18u / W'"
sa=0 sb=0 sd=0
model=nfet_03v3
spiceprefix=X
}
C {symbols/nfet_03v3.sym} 1730 -320 0 0 {name=M6
L=0.5u
W=50u
nf=10
m=3
ad="'int((nf+1)/2) * W/nf * 0.18u'"
pd="'2*int((nf+1)/2) * (W/nf + 0.18u)'"
as="'int((nf+2)/2) * W/nf * 0.18u'"
ps="'2*int((nf+2)/2) * (W/nf + 0.18u)'"
nrd="'0.18u / W'" nrs="'0.18u / W'"
sa=0 sb=0 sd=0
model=nfet_03v3
spiceprefix=X
}
C {res.sym} 1510 -120 0 0 {name=RS_EQ
value=3.3
footprint=1206
device=resistor
m=1
}
C {capa.sym} 1560 -120 0 0 {name=CS_EQ
m=1
value=12p
footprint=1206
device="ceramic capacitor"}
C {lab_pin.sym} 1560 -260 2 0 {name=p55 sig_type=std_logic lab=GND}
C {symbols/nfet_03v3.sym} 1520 -260 0 0 {name=M1
L=0.28u
W=20u
nf=10
m=6
ad="'int((nf+1)/2) * W/nf * 0.18u'"
pd="'2*int((nf+1)/2) * (W/nf + 0.18u)'"
as="'int((nf+2)/2) * W/nf * 0.18u'"
ps="'2*int((nf+2)/2) * (W/nf + 0.18u)'"
nrd="'0.18u / W'" nrs="'0.18u / W'"
sa=0 sb=0 sd=0
model=nfet_03v3
spiceprefix=X
}
C {lab_pin.sym} 951.25 -356.25 0 0 {name=p57 sig_type=std_logic lab=vbias_cas_cg}
C {vsource.sym} -360 21.25 2 0 {name=VBCS4 value=\{VBIAS_CAS_CG\} savecurrent=false}
C {lab_pin.sym} -360 81.25 3 0 {name=p58 sig_type=std_logic lab=vbias_cas_cg}
C {symbols/nfet_06v0.sym} 990 -356.25 0 0 {name=M7
L=0.6u
W=50u
nf=10
m=2
ad="'int((nf+1)/2) * W/nf * 0.18u'"
pd="'2*int((nf+1)/2) * (W/nf + 0.18u)'"
as="'int((nf+2)/2) * W/nf * 0.18u'"
ps="'2*int((nf+2)/2) * (W/nf + 0.18u)'"
nrd="'0.18u / W'" nrs="'0.18u / W'"
sa=0 sb=0 sd=0
model=nfet_06v0
spiceprefix=X
spice_ignore=short}
C {/home/arjun/eda/projects/The-Silent-Owl-GF180MCU-WB-LNA/analog_pad_sp_paramerters/xschem/gf180mcu_fd_io__asig_5p0.sym} 190 -820 0 0 {name=x1 model=gf180mcu_fd_io__asig_5p0
}
C {/home/arjun/eda/projects/The-Silent-Owl-GF180MCU-WB-LNA/analog_pad_sp_paramerters/xschem/gf180mcu_fd_io__asig_5p0.sym} 2630 -790 0 0 {name=x2 model=gf180mcu_fd_io__asig_5p0
}
C {code_shown.sym} 130 95 0 0 {name=MODELS1 only_toplevel=true
format="tcleval( @value )"
value="
.include $\{::180MCU_MODELS\}/design.ngspice

.lib $\{::180MCU_MODELS\}/sm141064.ngspice typical

.lib $\{::180MCU_MODELS\}/sm141064.ngspice res_typical
.lib $\{::180MCU_MODELS\}/sm141064.ngspice moscap_typical
.lib $\{::180MCU_MODELS\}/sm141064.ngspice diode_typical


.include /home/arjun/eda/pdks/gf180mcuD/libs.ref/gf180mcu_fd_io/spice/gf180mcu_fd_io.spice
*.include /home/arjun/eda/projects/The-Silent-Owl-GF180MCU-WB-LNA/analog_pad_sp_paramerters/spice_files/extracted_gf180mcu_fd_io__asig_5p0.spice
"}
C {lab_pin.sym} 1010 -311.25 2 0 {name=p42 sig_type=std_logic lab=vm2}
C {lab_pin.sym} 1030 -356.25 2 0 {name=p46 sig_type=std_logic lab=GND}
C {lab_pin.sym} 1540 -318.75 0 0 {name=p56 sig_type=std_logic lab=vm1}
C {symbols/pfet3_06v0.sym} 2060 -430 0 0 {name=M8
L=0.6u
W=50u
body=vdcbias
nf=10
m=9
ad="'int((nf+1)/2) * W/nf * 0.18u'"
pd="'2*int((nf+1)/2) * (W/nf + 0.18u)'"
as="'int((nf+2)/2) * W/nf * 0.18u'"
ps="'2*int((nf+2)/2) * (W/nf + 0.18u)'"
nrd="'0.18u / W'" nrs="'0.18u / W'"
sa=0 sb=0 sd=0
model=pfet_06v0
spiceprefix=X
spice_ignore=true}
C {lab_pin.sym} 2080 -530 0 0 {name=p59 sig_type=std_logic lab=vdcbias
spice_ignore=true}
C {lab_pin.sym} 2080 -370 0 0 {name=p60 sig_type=std_logic lab=vbuf
spice_ignore=true}
C {lab_pin.sym} 1540 -428.75 0 0 {name=p63 sig_type=std_logic lab=vm4}
C {lab_pin.sym} 2028.75 -430 1 0 {name=p64 sig_type=std_logic lab=vm4
spice_ignore=true}
C {code.sym} 2062.5 83.75 0 0 {name=s1 only_toplevel=false value="


* =============================================================================
* FIXED SUPPLY / PACKAGE VALUES
* =============================================================================

.param VDS=5.0
.param VDDIO_SUP=5.0
.param L_BW=2n
.param R_BW=0.2


* =============================================================================
* FIXED INPUT NETWORK
* =============================================================================

.param L_IN=1.80n
.param R_L_IN=1.5
.param CIN_VAL=100p
.param C_SH_IN=1f


* =============================================================================
* FIXED XM2 COMMON-GATE INPUT STAGE
* =============================================================================

.param VBIAS_CG=2.20
.param W_CG=140u
.param M_CG=2
.param L_CG=0.60u
.param RD1=760
.param RBIAS_CG=50k
.param CBYP_CG=20p


* =============================================================================
* FIXED MIXED-VOLTAGE XM1/XM4 STAGE
* =============================================================================

.param C12_VAL=33p

.param VBIAS_CS=0.95
.param W_CS=40u
.param M_CS=2
.param L_CS=0.28u
.param RBIAS_CS=50k

.param VBIAS_CAS=3.30
.param W_CAS=70u
.param M_CAS=1
.param L_CAS=0.60u
.param RD2=490

.param RS_EQ=7
.param CSEQ_VAL=12p


* =============================================================================
* FIXED BODY-TIED SOURCE FOLLOWER
* =============================================================================

.param W_SF=125u
.param M_SF=2
.param L_SF=0.60u
.param RG_SF_VAL=0.01


* =============================================================================
* FIXED OUTPUT NETWORK
* =============================================================================

.param COUT_VAL=56p
.param L_OUT=0.20n
.param R_L_OUT=1.5
.param C_SH_OUT=1f


* =============================================================================
* FIXED XM5 COMMON-GATE CURRENT SINK
* =============================================================================

.param VBIAS_ICG=1.55
.param L_BIAS_CG=0.50u
.param W_BIAS_CG=30u
.param M_BIAS_CG=1


* =============================================================================
* FIXED XM6 SOURCE-FOLLOWER CURRENT SINK
* =============================================================================

.param VBIAS_BUF=3.50
.param L_BIAS_SF=0.50u
.param W_BIAS_SF=50u
.param M_BIAS_SF=3


* =============================================================================
* XM7 CG-CASCODE SWEEP PARAMETERS
* =============================================================================

.param VBIAS_CAS_CG=3.40
.param L_CAS_CG=0.60u
.param W_CAS_CG=50u
.param M_CAS_CG=2

.control

set noaskquit
set wr_singlescale
set wr_vecnames
set numdgt=10

let target_gain_bw=10.0

echo ============================================================ > lna_core_06V_cgcs_report.txt
echo GF180MCU_LNA_CORE_06V_CGCS_DETAILED_REPORT >> lna_core_06V_cgcs_report.txt
echo TARGET_FREQUENCY_HZ 2.400e9 >> lna_core_06V_cgcs_report.txt
echo TARGET_BAND_HZ 2.300e9 2.500e9 >> lna_core_06V_cgcs_report.txt
echo GAIN_BANDWIDTH_THRESHOLD_DB 10.0 >> lna_core_06V_cgcs_report.txt
echo PORT_REFERENCE_OHM 50 >> lna_core_06V_cgcs_report.txt
echo ============================================================ >> lna_core_06V_cgcs_report.txt

* =============================================================================
* DC OPERATING POINT
* =============================================================================

op

let pdcop=1e3*(abs(i(VDD))*v(vdcbias)+abs(i(VDDIO))*v(vddio))
let icoreop=abs(i(VDD))
let iioop=abs(i(VDDIO))

let vsop=v(s)
let vdop=v(d)
let vnet3op=v(net3)
let vnet8op=v(net8)
let vbufop=v(vbuf)
let vgcsop=v(g_cs)
let vgcgop=v(g_cg)

let id1op=abs(@m.xm1.m0[id])
let gm1op=@m.xm1.m0[gm]
let gmb1op=@m.xm1.m0[gmbs]
let gds1op=@m.xm1.m0[gds]
let vgs1op=@m.xm1.m0[vgs]
let vds1op=@m.xm1.m0[vds]
let vbs1op=@m.xm1.m0[vbs]
let vth1op=@m.xm1.m0[vth]
let vov1op=vgs1op-vth1op
let vdsat1op=abs(@m.xm1.m0[vdsat])
let sat1op=vds1op-vdsat1op
let gmid1op=gm1op/(id1op+1e-30)
let ro1op=1/(gds1op+1e-30)

let id2op=abs(@m.xm2.m0[id])
let gm2op=@m.xm2.m0[gm]
let gmb2op=@m.xm2.m0[gmbs]
let gds2op=@m.xm2.m0[gds]
let vgs2op=@m.xm2.m0[vgs]
let vds2op=@m.xm2.m0[vds]
let vbs2op=@m.xm2.m0[vbs]
let vth2op=@m.xm2.m0[vth]
let vov2op=vgs2op-vth2op
let vdsat2op=abs(@m.xm2.m0[vdsat])
let sat2op=vds2op-vdsat2op
let gmid2op=gm2op/(id2op+1e-30)
let ro2op=1/(gds2op+1e-30)

let id4op=abs(@m.xm4.m0[id])
let gm4op=@m.xm4.m0[gm]
let gmb4op=@m.xm4.m0[gmbs]
let gds4op=@m.xm4.m0[gds]
let vgs4op=@m.xm4.m0[vgs]
let vds4op=@m.xm4.m0[vds]
let vbs4op=@m.xm4.m0[vbs]
let vth4op=@m.xm4.m0[vth]
let vov4op=vgs4op-vth4op
let vdsat4op=abs(@m.xm4.m0[vdsat])
let sat4op=vds4op-vdsat4op
let gmid4op=gm4op/(id4op+1e-30)
let ro4op=1/(gds4op+1e-30)

let id5op=abs(@m.xm5.m0[id])
let gm5op=@m.xm5.m0[gm]
let gmb5op=@m.xm5.m0[gmbs]
let gds5op=@m.xm5.m0[gds]
let vgs5op=@m.xm5.m0[vgs]
let vds5op=@m.xm5.m0[vds]
let vbs5op=@m.xm5.m0[vbs]
let vth5op=@m.xm5.m0[vth]
let vov5op=vgs5op-vth5op
let vdsat5op=abs(@m.xm5.m0[vdsat])
let sat5op=vds5op-vdsat5op
let gmid5op=gm5op/(id5op+1e-30)
let ro5op=1/(gds5op+1e-30)

let id7op=abs(@m.xm7.m0[id])
let gm7op=@m.xm7.m0[gm]
let gmb7op=@m.xm7.m0[gmbs]
let gds7op=@m.xm7.m0[gds]
let vgs7op=@m.xm7.m0[vgs]
let vds7op=@m.xm7.m0[vds]
let vbs7op=@m.xm7.m0[vbs]
let vth7op=@m.xm7.m0[vth]
let vov7op=vgs7op-vth7op
let vdsat7op=abs(@m.xm7.m0[vdsat])
let sat7op=vds7op-vdsat7op
let gmid7op=gm7op/(id7op+1e-30)
let ro7op=1/(gds7op+1e-30)

* PMOS Buffer XM8
let id8op=abs(@m.xm8.m0[id])
let gm8op=@m.xm8.m0[gm]
let gmb8op=@m.xm8.m0[gmbs]
let gds8op=@m.xm8.m0[gds]
let vgs8op=@m.xm8.m0[vgs]
let vds8op=@m.xm8.m0[vds]
let vbs8op=@m.xm8.m0[vbs]
let vth8op=@m.xm8.m0[vth]
let vov8op=vgs8op-vth8op
let vdsat8op=abs(@m.xm8.m0[vdsat])
let sat8op=vds8op-vdsat8op
let gmid8op=gm8op/(id8op+1e-30)
let ro8op=1/(gds8op+1e-30)

* Buffer Current Sink XM9
let id9op=abs(@m.xm9.m0[id])
let gm9op=@m.xm9.m0[gm]
let gmb9op=@m.xm9.m0[gmbs]
let gds9op=@m.xm9.m0[gds]
let vgs9op=@m.xm9.m0[vgs]
let vds9op=@m.xm9.m0[vds]
let vbs9op=@m.xm9.m0[vbs]
let vth9op=@m.xm9.m0[vth]
let vov9op=vgs9op-vth9op
let vdsat9op=abs(@m.xm9.m0[vdsat])
let sat9op=vds9op-vdsat9op
let gmid9op=gm9op/(id9op+1e-30)
let ro9op=1/(gds9op+1e-30)

let vnet9op=vnet3op+vds1op
let vnet9check=vnet8op-vds4op
let vnet9diff=vnet9op-vnet9check
let vnet10op=vsop+vds2op
let vnet10check=vdop-vds7op
let vnet10diff=vnet10op-vnet10check

set op_pdc=$&pdcop
set op_icore=$&icoreop
set op_iio=$&iioop
set op_vs=$&vsop
set op_vnet10=$&vnet10op
set op_vnet10check=$&vnet10check
set op_vnet10diff=$&vnet10diff
set op_vd=$&vdop
set op_vnet3=$&vnet3op
set op_vnet9=$&vnet9op
set op_vnet9check=$&vnet9check
set op_vnet9diff=$&vnet9diff
set op_vnet8=$&vnet8op
set op_vbuf=$&vbufop
set op_vgcs=$&vgcsop
set op_vgcg=$&vgcgop

set op_id1=$&id1op
set op_gm1=$&gm1op
set op_gmb1=$&gmb1op
set op_gds1=$&gds1op
set op_vgs1=$&vgs1op
set op_vds1=$&vds1op
set op_vbs1=$&vbs1op
set op_vth1=$&vth1op
set op_vov1=$&vov1op
set op_vdsat1=$&vdsat1op
set op_sat1=$&sat1op
set op_gmid1=$&gmid1op
set op_ro1=$&ro1op

set op_id2=$&id2op
set op_gm2=$&gm2op
set op_gmb2=$&gmb2op
set op_gds2=$&gds2op
set op_vgs2=$&vgs2op
set op_vds2=$&vds2op
set op_vbs2=$&vbs2op
set op_vth2=$&vth2op
set op_vov2=$&vov2op
set op_vdsat2=$&vdsat2op
set op_sat2=$&sat2op
set op_gmid2=$&gmid2op
set op_ro2=$&ro2op

set op_id4=$&id4op
set op_gm4=$&gm4op
set op_gmb4=$&gmb4op
set op_gds4=$&gds4op
set op_vgs4=$&vgs4op
set op_vds4=$&vds4op
set op_vbs4=$&vbs4op
set op_vth4=$&vth4op
set op_vov4=$&vov4op
set op_vdsat4=$&vdsat4op
set op_sat4=$&sat4op
set op_gmid4=$&gmid4op
set op_ro4=$&ro4op

set op_id5=$&id5op
set op_gm5=$&gm5op
set op_gmb5=$&gmb5op
set op_gds5=$&gds5op
set op_vgs5=$&vgs5op
set op_vds5=$&vds5op
set op_vbs5=$&vbs5op
set op_vth5=$&vth5op
set op_vov5=$&vov5op
set op_vdsat5=$&vdsat5op
set op_sat5=$&sat5op
set op_gmid5=$&gmid5op
set op_ro5=$&ro5op

set op_id7=$&id7op
set op_gm7=$&gm7op
set op_gmb7=$&gmb7op
set op_gds7=$&gds7op
set op_vgs7=$&vgs7op
set op_vds7=$&vds7op
set op_vbs7=$&vbs7op
set op_vth7=$&vth7op
set op_vov7=$&vov7op
set op_vdsat7=$&vdsat7op
set op_sat7=$&sat7op
set op_gmid7=$&gmid7op
set op_ro7=$&ro7op

set op_id8=$&id8op
set op_gm8=$&gm8op
set op_gmb8=$&gmb8op
set op_gds8=$&gds8op
set op_vgs8=$&vgs8op
set op_vds8=$&vds8op
set op_vbs8=$&vbs8op
set op_vth8=$&vth8op
set op_vov8=$&vov8op
set op_vdsat8=$&vdsat8op
set op_sat8=$&sat8op
set op_gmid8=$&gmid8op
set op_ro8=$&ro8op

set op_id9=$&id9op
set op_gm9=$&gm9op
set op_gmb9=$&gmb9op
set op_gds9=$&gds9op
set op_vgs9=$&vgs9op
set op_vds9=$&vds9op
set op_vbs9=$&vbs9op
set op_vth9=$&vth9op
set op_vov9=$&vov9op
set op_vdsat9=$&vdsat9op
set op_sat9=$&sat9op
set op_gmid9=$&gmid9op
set op_ro9=$&ro9op

echo ============================================================ >> lna_core_06V_cgcs_report.txt
echo DC_SUPPLY_AND_NODE_VOLTAGES >> lna_core_06V_cgcs_report.txt
echo PDC_mW $op_pdc ICORE_A $op_icore IIO_A $op_iio >> lna_core_06V_cgcs_report.txt
echo NODES_V S $op_vs NET10_DERIVED $op_vnet10 D $op_vd NET3 $op_vnet3 NET9_DERIVED $op_vnet9 NET8 $op_vnet8 VBUF $op_vbuf G_CS $op_vgcs G_CG $op_vgcg >> lna_core_06V_cgcs_report.txt
echo HIDDEN_NODE_CHECKS NET10_FROM_XM2 $op_vnet10 NET10_FROM_XM7 $op_vnet10check DIFFERENCE $op_vnet10diff NET9_FROM_XM1 $op_vnet9 NET9_FROM_XM4 $op_vnet9check DIFFERENCE $op_vnet9diff >> lna_core_06V_cgcs_report.txt
echo ============================================================ >> lna_core_06V_cgcs_report.txt
echo TRANSISTOR_OPERATING_POINTS >> lna_core_06V_cgcs_report.txt
echo FIELDS ID_A GM_S GMBS_S GDS_S VGS_V VDS_V VBS_V VTH_V VOV_V VDSAT_V SAT_MARGIN_V GM_OVER_ID_1_PER_V RO_OHM >> lna_core_06V_cgcs_report.txt
echo XM1_CS ID $op_id1 GM $op_gm1 GMBS $op_gmb1 GDS $op_gds1 VGS $op_vgs1 VDS $op_vds1 VBS $op_vbs1 VTH $op_vth1 VOV $op_vov1 VDSAT $op_vdsat1 SAT_MARGIN $op_sat1 GMID $op_gmid1 RO $op_ro1 >> lna_core_06V_cgcs_report.txt
echo XM2_CG ID $op_id2 GM $op_gm2 GMBS $op_gmb2 GDS $op_gds2 VGS $op_vgs2 VDS $op_vds2 VBS $op_vbs2 VTH $op_vth2 VOV $op_vov2 VDSAT $op_vdsat2 SAT_MARGIN $op_sat2 GMID $op_gmid2 RO $op_ro2 >> lna_core_06V_cgcs_report.txt
echo XM4_CS_CASCODE ID $op_id4 GM $op_gm4 GMBS $op_gmb4 GDS $op_gds4 VGS $op_vgs4 VDS $op_vds4 VBS $op_vbs4 VTH $op_vth4 VOV $op_vov4 VDSAT $op_vdsat4 SAT_MARGIN $op_sat4 GMID $op_gmid4 RO $op_ro4 >> lna_core_06V_cgcs_report.txt
echo XM5_CG_CURRENT_SINK ID $op_id5 GM $op_gm5 GMBS $op_gmb5 GDS $op_gds5 VGS $op_vgs5 VDS $op_vds5 VBS $op_vbs5 VTH $op_vth5 VOV $op_vov5 VDSAT $op_vdsat5 SAT_MARGIN $op_sat5 GMID $op_gmid5 RO $op_ro5 >> lna_core_06V_cgcs_report.txt
echo XM7_CG_CASCODE ID $op_id7 GM $op_gm7 GMBS $op_gmb7 GDS $op_gds7 VGS $op_vgs7 VDS $op_vds7 VBS $op_vbs7 VTH $op_vth7 VOV $op_vov7 VDSAT $op_vdsat7 SAT_MARGIN $op_sat7 GMID $op_gmid7 RO $op_ro7 >> lna_core_06V_cgcs_report.txt
echo XM8_PMOS_BUFFER ID $op_id8 GM $op_gm8 GMBS $op_gmb8 GDS $op_gds8 VGS $op_vgs8 VDS $op_vds8 VBS $op_vbs8 VTH $op_vth8 VOV $op_vov8 VDSAT $op_vdsat8 SAT_MARGIN $op_sat8 GMID $op_gmid8 RO $op_ro8 >> lna_core_06V_cgcs_report.txt
echo XM9_BUFFER_CURRENT_SINK ID $op_id9 GM $op_gm9 GMBS $op_gmb9 GDS $op_gds9 VGS $op_vgs9 VDS $op_vds9 VBS $op_vbs9 VTH $op_vth9 VOV $op_vov9 VDSAT $op_vdsat9 SAT_MARGIN $op_sat9 GMID $op_gmid9 RO $op_ro9 >> lna_core_06V_cgcs_report.txt

destroy $curplot

* =============================================================================
* SINGLE BROADBAND RF ANALYSIS
* One reset and one SP run are used for all 1 MHz to 7 GHz RF results.
* Target-band values are extracted from the same dataset.
* This avoids inconsistent port excitation state between repeated SP runs.
* 7000 points from 1 MHz to 7 GHz gives exactly 1 MHz spacing.
* =============================================================================

reset
sp lin 7000 1Meg 7Gig 1
set rfplot=$curplot

let fghz=frequency/1e9

let s11db=db(s_1_1)
let s21db=db(s_2_1)
let s12db=db(s_1_2)
let s22db=db(s_2_2)

let s11re=real(s_1_1)
let s11im=imag(s_1_1)
let s21re=real(s_2_1)
let s21im=imag(s_2_1)
let s12re=real(s_1_2)
let s12im=imag(s_1_2)
let s22re=real(s_2_2)
let s22im=imag(s_2_2)

let nfdb=real(NF)
let nfmin_db=real(NFmin)

let delta=s_1_1*s_2_2-s_1_2*s_2_1
let delta_mag=mag(delta)
let a11=mag(s_1_1)
let a12=mag(s_1_2)
let a21=mag(s_2_1)
let a22=mag(s_2_2)
let mu=(1-a11*a11)/(mag(s_2_2-delta*conj(s_1_1))+mag(s_1_2*s_2_1))
let mup=(1-a22*a22)/(mag(s_1_1-delta*conj(s_2_2))+mag(s_1_2*s_2_1))
let kval=(1-a11*a11-a22*a22+delta_mag*delta_mag)/(2*a12*a21)

let zin=50*(1+s_1_1)/(1-s_1_1)
let zout=50*(1+s_2_2)/(1-s_2_2)
let zin_re=real(zin)
let zin_im=imag(zin)
let zout_re=real(zout)
let zout_im=imag(zout)

let npts=length(frequency)

* Find indices nearest 2.300 GHz, 2.400 GHz and 2.500 GHz.
let ilo=0
let icenter=0
let ihi=0
let errlo=abs(frequency[0]-2.3e9)
let errcenter=abs(frequency[0]-2.4e9)
let errhi=abs(frequency[0]-2.5e9)
let ii=1
while ii < npts
let newerr=abs(frequency[ii]-2.3e9)
if newerr < errlo
let errlo=newerr
let ilo=ii
end
let newerr=abs(frequency[ii]-2.4e9)
if newerr < errcenter
let errcenter=newerr
let icenter=ii
end
let newerr=abs(frequency[ii]-2.5e9)
if newerr < errhi
let errhi=newerr
let ihi=ii
end
let ii=ii+1
end

* Values at the sample nearest 2.400 GHz.
let center_freq=frequency[icenter]
let s11c=s11db[icenter]
let s21c=s21db[icenter]
let s12c=s12db[icenter]
let s22c=s22db[icenter]
let s11rc=s11re[icenter]
let s11ic=s11im[icenter]
let s21rc=s21re[icenter]
let s21ic=s21im[icenter]
let s12rc=s12re[icenter]
let s12ic=s12im[icenter]
let s22rc=s22re[icenter]
let s22ic=s22im[icenter]
let nfc=nfdb[icenter]
let nfminc=nfmin_db[icenter]
let muc=mu[icenter]
let mupc=mup[icenter]
let kc=kval[icenter]
let dmc=delta_mag[icenter]
let zinrc=zin_re[icenter]
let zinic=zin_im[icenter]
let zoutrc=zout_re[icenter]
let zoutic=zout_im[icenter]

* Initialize target-band extrema.
let s11min=s11db[ilo]
let s11max=s11db[ilo]
let s21min=s21db[ilo]
let s21max=s21db[ilo]
let s12min=s12db[ilo]
let s12max=s12db[ilo]
let s22min=s22db[ilo]
let s22max=s22db[ilo]
let nfbandmin=nfdb[ilo]
let nfbandmax=nfdb[ilo]
let nfminbandmin=nfmin_db[ilo]
let nfminbandmax=nfmin_db[ilo]
let mumin=mu[ilo]
let mupmin=mup[ilo]
let kmin=kval[ilo]
let dmax=delta_mag[ilo]

let s11min_i=ilo
let s11max_i=ilo
let s21min_i=ilo
let s21max_i=ilo
let s12min_i=ilo
let s12max_i=ilo
let s22min_i=ilo
let s22max_i=ilo
let nfmin_i=ilo
let nfmax_i=ilo
let nfminpar_min_i=ilo
let nfminpar_max_i=ilo
let mumin_i=ilo
let mupmin_i=ilo
let kmin_i=ilo
let dmax_i=ilo

* Scan 2.300 GHz to 2.500 GHz.
let ii=ilo
while ii <= ihi
if s11db[ii] < s11min
let s11min=s11db[ii]
let s11min_i=ii
end
if s11db[ii] > s11max
let s11max=s11db[ii]
let s11max_i=ii
end
if s21db[ii] < s21min
let s21min=s21db[ii]
let s21min_i=ii
end
if s21db[ii] > s21max
let s21max=s21db[ii]
let s21max_i=ii
end
if s12db[ii] < s12min
let s12min=s12db[ii]
let s12min_i=ii
end
if s12db[ii] > s12max
let s12max=s12db[ii]
let s12max_i=ii
end
if s22db[ii] < s22min
let s22min=s22db[ii]
let s22min_i=ii
end
if s22db[ii] > s22max
let s22max=s22db[ii]
let s22max_i=ii
end
if nfdb[ii] < nfbandmin
let nfbandmin=nfdb[ii]
let nfmin_i=ii
end
if nfdb[ii] > nfbandmax
let nfbandmax=nfdb[ii]
let nfmax_i=ii
end
if nfmin_db[ii] < nfminbandmin
let nfminbandmin=nfmin_db[ii]
let nfminpar_min_i=ii
end
if nfmin_db[ii] > nfminbandmax
let nfminbandmax=nfmin_db[ii]
let nfminpar_max_i=ii
end
if mu[ii] < mumin
let mumin=mu[ii]
let mumin_i=ii
end
if mup[ii] < mupmin
let mupmin=mup[ii]
let mupmin_i=ii
end
if kval[ii] < kmin
let kmin=kval[ii]
let kmin_i=ii
end
if delta_mag[ii] > dmax
let dmax=delta_mag[ii]
let dmax_i=ii
end
let ii=ii+1
end

let gain_ripple=s21max-s21min

let s11min_f=frequency[s11min_i]
let s11max_f=frequency[s11max_i]
let s21min_f=frequency[s21min_i]
let s21max_f=frequency[s21max_i]
let s12min_f=frequency[s12min_i]
let s12max_f=frequency[s12max_i]
let s22min_f=frequency[s22min_i]
let s22max_f=frequency[s22max_i]
let nfmin_f=frequency[nfmin_i]
let nfmax_f=frequency[nfmax_i]
let nfminpar_min_f=frequency[nfminpar_min_i]
let nfminpar_max_f=frequency[nfminpar_max_i]
let mumin_f=frequency[mumin_i]
let mupmin_f=frequency[mupmin_i]
let kmin_f=frequency[kmin_i]
let dmax_f=frequency[dmax_i]

* Find the broadband S21 peak and its index.
let imax=0
let gainmax=s21db[0]
let ii=1
while ii < npts
if s21db[ii] > gainmax
let gainmax=s21db[ii]
let imax=ii
end
let ii=ii+1
end
let peakfreq=frequency[imax]

echo ============================================================ >> lna_core_06V_cgcs_report.txt
echo RF_AT_2P400_GHZ_FROM_SINGLE_BROADBAND_SWEEP >> lna_core_06V_cgcs_report.txt
echo ACTUAL_SAMPLE_HZ $&center_freq >> lna_core_06V_cgcs_report.txt
echo S11_DB $&s11c REAL $&s11rc IMAG $&s11ic >> lna_core_06V_cgcs_report.txt
echo S21_DB $&s21c REAL $&s21rc IMAG $&s21ic >> lna_core_06V_cgcs_report.txt
echo S12_DB $&s12c REAL $&s12rc IMAG $&s12ic >> lna_core_06V_cgcs_report.txt
echo S22_DB $&s22c REAL $&s22rc IMAG $&s22ic >> lna_core_06V_cgcs_report.txt
echo NF_DB $&nfc NFMIN_DB $&nfminc >> lna_core_06V_cgcs_report.txt
echo MU $&muc MUP $&mupc K $&kc DELTA_MAG $&dmc >> lna_core_06V_cgcs_report.txt
echo ZIN_OHM RE $&zinrc IM $&zinic >> lna_core_06V_cgcs_report.txt
echo ZOUT_OHM RE $&zoutrc IM $&zoutic >> lna_core_06V_cgcs_report.txt

echo ============================================================ >> lna_core_06V_cgcs_report.txt
echo RF_MIN_MAX_FROM_2P300_TO_2P500_GHZ >> lna_core_06V_cgcs_report.txt
echo S11_MIN_DB $&s11min AT_HZ $&s11min_f S11_MAX_DB $&s11max AT_HZ $&s11max_f >> lna_core_06V_cgcs_report.txt
echo S21_MIN_DB $&s21min AT_HZ $&s21min_f S21_MAX_DB $&s21max AT_HZ $&s21max_f GAIN_RIPPLE_DB $&gain_ripple >> lna_core_06V_cgcs_report.txt
echo S12_MIN_DB $&s12min AT_HZ $&s12min_f S12_MAX_DB $&s12max AT_HZ $&s12max_f >> lna_core_06V_cgcs_report.txt
echo S22_MIN_DB $&s22min AT_HZ $&s22min_f S22_MAX_DB $&s22max AT_HZ $&s22max_f >> lna_core_06V_cgcs_report.txt
echo NF_MIN_DB $&nfbandmin AT_HZ $&nfmin_f NF_MAX_DB $&nfbandmax AT_HZ $&nfmax_f >> lna_core_06V_cgcs_report.txt
echo NFMIN_PARAMETER_MIN_DB $&nfminbandmin AT_HZ $&nfminpar_min_f NFMIN_PARAMETER_MAX_DB $&nfminbandmax AT_HZ $&nfminpar_max_f >> lna_core_06V_cgcs_report.txt
echo MU_MIN $&mumin AT_HZ $&mumin_f MUP_MIN $&mupmin AT_HZ $&mupmin_f >> lna_core_06V_cgcs_report.txt
echo K_MIN $&kmin AT_HZ $&kmin_f DELTA_MAX $&dmax AT_HZ $&dmax_f >> lna_core_06V_cgcs_report.txt

echo ============================================================ >> lna_core_06V_cgcs_report.txt
echo BROADBAND_GAIN_CHECK_1MHZ_TO_7GHZ >> lna_core_06V_cgcs_report.txt
echo GAIN_AT_2P4_DB $&s21c >> lna_core_06V_cgcs_report.txt
echo BROADBAND_PEAK_HZ $&peakfreq PEAK_GAIN_DB $&gainmax >> lna_core_06V_cgcs_report.txt

echo ============================================================ >> lna_core_06V_cgcs_report.txt
echo TARGET_CENTERED_S21_GE_10DB_BAND >> lna_core_06V_cgcs_report.txt
if s21c >= 10.0
let bwlo=icenter
let bwhi=icenter
let search=1
while search = 1
if bwlo > 0
if s21db[bwlo-1] >= 10.0
let bwlo=bwlo-1
else
let search=0
end
else
let search=0
end
end
let search=1
while search = 1
if bwhi < npts-1
if s21db[bwhi+1] >= 10.0
let bwhi=bwhi+1
else
let search=0
end
else
let search=0
end
end
let bwflo=frequency[bwlo]
let bwfhi=frequency[bwhi]
let bwval=bwfhi-bwflo
let bwcenter=0.5*(bwfhi+bwflo)
let bwfbw=100*bwval/(bwcenter+1e-30)
echo LOWER_HZ $&bwflo UPPER_HZ $&bwfhi BANDWIDTH_HZ $&bwval BAND_CENTER_HZ $&bwcenter FRACTIONAL_BW_PERCENT $&bwfbw >> lna_core_06V_cgcs_report.txt
else
echo NO_VALID_TARGET_CENTERED_BAND S21_AT_2P4_DB $&s21c >> lna_core_06V_cgcs_report.txt
end

echo ============================================================ >> lna_core_06V_cgcs_report.txt
echo GLOBAL_CONTIGUOUS_S21_GE_10DB_BAND_AROUND_PEAK >> lna_core_06V_cgcs_report.txt
if gainmax >= 10.0
let bwlo=imax
let bwhi=imax
let search=1
while search = 1
if bwlo > 0
if s21db[bwlo-1] >= 10.0
let bwlo=bwlo-1
else
let search=0
end
else
let search=0
end
end
let search=1
while search = 1
if bwhi < npts-1
if s21db[bwhi+1] >= 10.0
let bwhi=bwhi+1
else
let search=0
end
else
let search=0
end
end
let bwflo=frequency[bwlo]
let bwfhi=frequency[bwhi]

let bwval=bwfhi-bwflo
let bwcenter=0.5*(bwfhi+bwflo)
let bwfbw=100*bwval/(bwcenter+1e-30)
echo LOWER_HZ $&bwflo UPPER_HZ $&bwfhi BANDWIDTH_HZ $&bwval BAND_CENTER_HZ $&bwcenter FRACTIONAL_BW_PERCENT $&bwfbw >> lna_core_06V_cgcs_report.txt
else
echo NO_S21_ABOVE_10DB_FROM_1MHZ_TO_7GHZ PEAK_GAIN_DB $&gainmax PEAK_FREQUENCY_HZ $&peakfreq >> lna_core_06V_cgcs_report.txt
end

wrdata lna_core_06V_cgcs_target_band.dat frequency s_1_1 s_2_1 s_1_2 s_2_2 s11db s21db s12db s22db nfdb nfmin_db kval mu mup delta_mag zin_re zin_im zout_re zout_im
wrdata lna_core_06V_cgcs_broadband.dat frequency s11db s21db s12db s22db nfdb nfmin_db kval mu mup delta_mag zin_re zin_im zout_re zout_im

* =============================================================================
* WIDEBAND STABILITY 10 MHZ TO 30 GHZ
* =============================================================================

sp dec 101 10Meg 30G 1
set stabilityplot=$curplot

let wbdelta=s_1_1*s_2_2-s_1_2*s_2_1
let wbmd=mag(wbdelta)
let wba11=mag(s_1_1)
let wba12=mag(s_1_2)
let wba21=mag(s_2_1)
let wba22=mag(s_2_2)
let wbmu=(1-wba11*wba11)/(mag(s_2_2-wbdelta*conj(s_1_1))+mag(s_1_2*s_2_1))
let wbmup=(1-wba22*wba22)/(mag(s_1_1-wbdelta*conj(s_2_2))+mag(s_1_2*s_2_1))
let wbk=(1-wba11*wba11-wba22*wba22+wbmd*wbmd)/(2*wba12*wba21)

let wbkmin=minimum(wbk)
let wbmumin=minimum(wbmu)
let wbmupmin=minimum(wbmup)
let wbdmax=maximum(wbmd)

set final_wbkmin=$&wbkmin
set final_wbmumin=$&wbmumin
set final_wbmupmin=$&wbmupmin
set final_wbdmax=$&wbdmax

echo ============================================================ >> lna_core_06V_cgcs_report.txt
echo WIDEBAND_STABILITY_10MHZ_TO_30GHZ >> lna_core_06V_cgcs_report.txt
echo K_MIN $final_wbkmin MU_MIN $final_wbmumin MUP_MIN $final_wbmupmin DELTA_MAX $final_wbdmax >> lna_core_06V_cgcs_report.txt

wrdata lna_core_06V_cgcs_stability.dat frequency wbk wbmu wbmup wbmd

let wbfghz=frequency/1e9

echo ============================================================ >> lna_core_06V_cgcs_report.txt
echo OUTPUT_FILES >> lna_core_06V_cgcs_report.txt
echo REPORT lna_core_06V_cgcs_report.txt >> lna_core_06V_cgcs_report.txt
echo TARGET_DATA lna_core_06V_cgcs_target_band.dat >> lna_core_06V_cgcs_report.txt
echo BROADBAND_DATA lna_core_06V_cgcs_broadband.dat >> lna_core_06V_cgcs_report.txt
echo STABILITY_DATA lna_core_06V_cgcs_stability.dat >> lna_core_06V_cgcs_report.txt
echo PLOTS S11_S21_S12_S22_SEPARATE NF_AND_NFMIN_TOGETHER STABILITY_AND_IMPEDANCE_DIAGNOSTICS >> lna_core_06V_cgcs_report.txt
echo ============================================================ >> lna_core_06V_cgcs_report.txt

* =============================================================================
* VISIBLE PLOTS
* Plot commands are intentionally placed at the very end.
* Neither rfplot nor stabilityplot is destroyed or reset afterward.
* =============================================================================

setplot $rfplot
setscale fghz

* Target band 2.3 GHz to 2.5 GHz
plot s11db xlimit 2.3 2.5
plot s21db xlimit 2.3 2.5
plot s12db xlimit 2.3 2.5
plot s22db xlimit 2.3 2.5
plot nfdb nfmin_db xlimit 2.3 2.5
plot mu mup xlimit 2.3 2.5
plot kval xlimit 2.3 2.5
plot delta_mag xlimit 2.3 2.5
plot zin_re zin_im xlimit 2.3 2.5
plot zout_re zout_im xlimit 2.3 2.5

* Broadband 1 MHz to 7 GHz
plot s11db xlimit 0 7
plot s21db xlimit 0 7
plot s12db xlimit 0 7
plot s22db xlimit 0 7
plot nfdb nfmin_db xlimit 0 7
plot mu mup xlimit 0 7
plot kval xlimit 0 7
plot delta_mag xlimit 0 7
plot zin_re zin_im xlimit 0 7
plot zout_re zout_im xlimit 0 7

* Wideband stability 10 MHz to 30 GHz
setplot $stabilityplot
setscale wbfghz
plot wbmu wbmup
plot wbk
plot wbmd

.endc

"
spice_ignore=true}
C {lab_pin.sym} 2080 -240 3 0 {name=p61 sig_type=std_logic lab=GND
spice_ignore=true}
C {res.sym} 2080 -300 0 0 {name=R1
value=3000
footprint=1206
device=resistor
m=1
spice_ignore=true}
C {ind.sym} 1420 -520 2 0 {name=LBW_IN2
m=1
value=3.3n
footprint=1206
device=inductor}
C {capa.sym} 1630 -520 0 0 {name=CS_EQ1
m=1
value=1p
footprint=1206
device="ceramic capacitor"}
C {res.sym} 1420 -430 0 0 {name=RS_EQ1
value=3
footprint=1206
device=resistor
m=1
spice_ignore=short}
